VERSION 5.7 ;
  NOWIREEXTENSIONATPIN ON ;
  DIVIDERCHAR "/" ;
  BUSBITCHARS "[]" ;
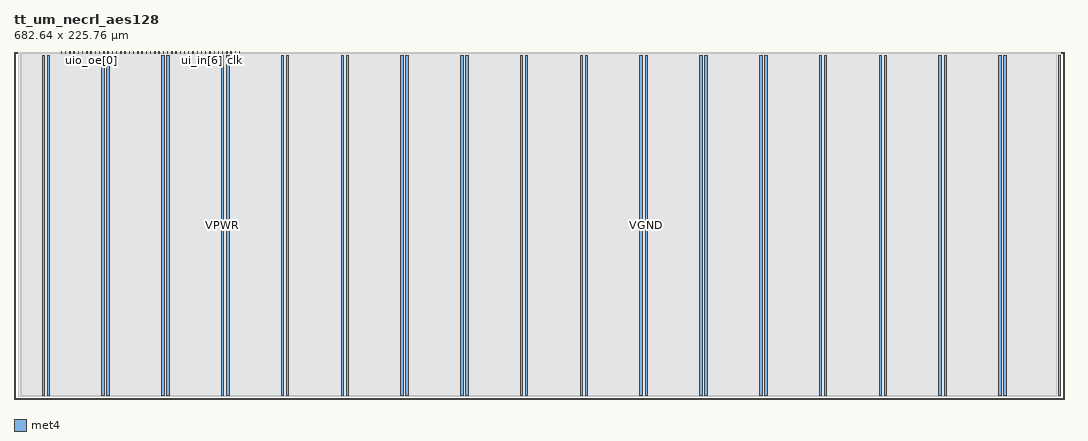
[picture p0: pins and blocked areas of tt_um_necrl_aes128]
MACRO tt_um_necrl_aes128
  CLASS BLOCK ;
  FOREIGN tt_um_necrl_aes128 ;
  ORIGIN 0.000 0.000 ;
  SIZE 682.640 BY 225.760 ;
  PIN VGND
    DIRECTION INOUT ;
    USE GROUND ;
    PORT
      LAYER met4 ;
        RECT 21.580 2.480 23.180 223.280 ;
    END
    PORT
      LAYER met4 ;
        RECT 60.450 2.480 62.050 223.280 ;
    END
    PORT
      LAYER met4 ;
        RECT 99.320 2.480 100.920 223.280 ;
    END
    PORT
      LAYER met4 ;
        RECT 138.190 2.480 139.790 223.280 ;
    END
    PORT
      LAYER met4 ;
        RECT 177.060 2.480 178.660 223.280 ;
    END
    PORT
      LAYER met4 ;
        RECT 215.930 2.480 217.530 223.280 ;
    END
    PORT
      LAYER met4 ;
        RECT 254.800 2.480 256.400 223.280 ;
    END
    PORT
      LAYER met4 ;
        RECT 293.670 2.480 295.270 223.280 ;
    END
    PORT
      LAYER met4 ;
        RECT 332.540 2.480 334.140 223.280 ;
    END
    PORT
      LAYER met4 ;
        RECT 371.410 2.480 373.010 223.280 ;
    END
    PORT
      LAYER met4 ;
        RECT 410.280 2.480 411.880 223.280 ;
    END
    PORT
      LAYER met4 ;
        RECT 449.150 2.480 450.750 223.280 ;
    END
    PORT
      LAYER met4 ;
        RECT 488.020 2.480 489.620 223.280 ;
    END
    PORT
      LAYER met4 ;
        RECT 526.890 2.480 528.490 223.280 ;
    END
    PORT
      LAYER met4 ;
        RECT 565.760 2.480 567.360 223.280 ;
    END
    PORT
      LAYER met4 ;
        RECT 604.630 2.480 606.230 223.280 ;
    END
    PORT
      LAYER met4 ;
        RECT 643.500 2.480 645.100 223.280 ;
    END
  END VGND
  PIN VPWR
    DIRECTION INOUT ;
    USE POWER ;
    PORT
      LAYER met4 ;
        RECT 18.280 2.480 19.880 223.280 ;
    END
    PORT
      LAYER met4 ;
        RECT 57.150 2.480 58.750 223.280 ;
    END
    PORT
      LAYER met4 ;
        RECT 96.020 2.480 97.620 223.280 ;
    END
    PORT
      LAYER met4 ;
        RECT 134.890 2.480 136.490 223.280 ;
    END
    PORT
      LAYER met4 ;
        RECT 173.760 2.480 175.360 223.280 ;
    END
    PORT
      LAYER met4 ;
        RECT 212.630 2.480 214.230 223.280 ;
    END
    PORT
      LAYER met4 ;
        RECT 251.500 2.480 253.100 223.280 ;
    END
    PORT
      LAYER met4 ;
        RECT 290.370 2.480 291.970 223.280 ;
    END
    PORT
      LAYER met4 ;
        RECT 329.240 2.480 330.840 223.280 ;
    END
    PORT
      LAYER met4 ;
        RECT 368.110 2.480 369.710 223.280 ;
    END
    PORT
      LAYER met4 ;
        RECT 406.980 2.480 408.580 223.280 ;
    END
    PORT
      LAYER met4 ;
        RECT 445.850 2.480 447.450 223.280 ;
    END
    PORT
      LAYER met4 ;
        RECT 484.720 2.480 486.320 223.280 ;
    END
    PORT
      LAYER met4 ;
        RECT 523.590 2.480 525.190 223.280 ;
    END
    PORT
      LAYER met4 ;
        RECT 562.460 2.480 564.060 223.280 ;
    END
    PORT
      LAYER met4 ;
        RECT 601.330 2.480 602.930 223.280 ;
    END
    PORT
      LAYER met4 ;
        RECT 640.200 2.480 641.800 223.280 ;
    END
    PORT
      LAYER met4 ;
        RECT 679.070 2.480 680.670 223.280 ;
    END
  END VPWR
  PIN clk
    DIRECTION INPUT ;
    USE SIGNAL ;
    PORT
      LAYER met4 ;
        RECT 143.830 224.760 144.130 225.760 ;
    END
  END clk
  PIN ena
    DIRECTION INPUT ;
    USE SIGNAL ;
    PORT
      LAYER met4 ;
        RECT 146.590 224.760 146.890 225.760 ;
    END
  END ena
  PIN rst_n
    DIRECTION INPUT ;
    USE SIGNAL ;
    PORT
      LAYER met4 ;
        RECT 141.070 224.760 141.370 225.760 ;
    END
  END rst_n
  PIN ui_in[0]
    DIRECTION INPUT ;
    USE SIGNAL ;
    PORT
      LAYER met4 ;
        RECT 138.310 224.760 138.610 225.760 ;
    END
  END ui_in[0]
  PIN ui_in[1]
    DIRECTION INPUT ;
    USE SIGNAL ;
    PORT
      LAYER met4 ;
        RECT 135.550 224.760 135.850 225.760 ;
    END
  END ui_in[1]
  PIN ui_in[2]
    DIRECTION INPUT ;
    USE SIGNAL ;
    PORT
      LAYER met4 ;
        RECT 132.790 224.760 133.090 225.760 ;
    END
  END ui_in[2]
  PIN ui_in[3]
    DIRECTION INPUT ;
    USE SIGNAL ;
    PORT
      LAYER met4 ;
        RECT 130.030 224.760 130.330 225.760 ;
    END
  END ui_in[3]
  PIN ui_in[4]
    DIRECTION INPUT ;
    USE SIGNAL ;
    PORT
      LAYER met4 ;
        RECT 127.270 224.760 127.570 225.760 ;
    END
  END ui_in[4]
  PIN ui_in[5]
    DIRECTION INPUT ;
    USE SIGNAL ;
    PORT
      LAYER met4 ;
        RECT 124.510 224.760 124.810 225.760 ;
    END
  END ui_in[5]
  PIN ui_in[6]
    DIRECTION INPUT ;
    USE SIGNAL ;
    PORT
      LAYER met4 ;
        RECT 121.750 224.760 122.050 225.760 ;
    END
  END ui_in[6]
  PIN ui_in[7]
    DIRECTION INPUT ;
    USE SIGNAL ;
    PORT
      LAYER met4 ;
        RECT 118.990 224.760 119.290 225.760 ;
    END
  END ui_in[7]
  PIN uio_in[0]
    DIRECTION INPUT ;
    USE SIGNAL ;
    PORT
      LAYER met4 ;
        RECT 116.230 224.760 116.530 225.760 ;
    END
  END uio_in[0]
  PIN uio_in[1]
    DIRECTION INPUT ;
    USE SIGNAL ;
    PORT
      LAYER met4 ;
        RECT 113.470 224.760 113.770 225.760 ;
    END
  END uio_in[1]
  PIN uio_in[2]
    DIRECTION INPUT ;
    USE SIGNAL ;
    PORT
      LAYER met4 ;
        RECT 110.710 224.760 111.010 225.760 ;
    END
  END uio_in[2]
  PIN uio_in[3]
    DIRECTION INPUT ;
    USE SIGNAL ;
    PORT
      LAYER met4 ;
        RECT 107.950 224.760 108.250 225.760 ;
    END
  END uio_in[3]
  PIN uio_in[4]
    DIRECTION INPUT ;
    USE SIGNAL ;
    PORT
      LAYER met4 ;
        RECT 105.190 224.760 105.490 225.760 ;
    END
  END uio_in[4]
  PIN uio_in[5]
    DIRECTION INPUT ;
    USE SIGNAL ;
    PORT
      LAYER met4 ;
        RECT 102.430 224.760 102.730 225.760 ;
    END
  END uio_in[5]
  PIN uio_in[6]
    DIRECTION INPUT ;
    USE SIGNAL ;
    PORT
      LAYER met4 ;
        RECT 99.670 224.760 99.970 225.760 ;
    END
  END uio_in[6]
  PIN uio_in[7]
    DIRECTION INPUT ;
    USE SIGNAL ;
    PORT
      LAYER met4 ;
        RECT 96.910 224.760 97.210 225.760 ;
    END
  END uio_in[7]
  PIN uio_oe[0]
    DIRECTION OUTPUT ;
    USE SIGNAL ;
    PORT
      LAYER met4 ;
        RECT 49.990 224.760 50.290 225.760 ;
    END
  END uio_oe[0]
  PIN uio_oe[1]
    DIRECTION OUTPUT ;
    USE SIGNAL ;
    PORT
      LAYER met4 ;
        RECT 47.230 224.760 47.530 225.760 ;
    END
  END uio_oe[1]
  PIN uio_oe[2]
    DIRECTION OUTPUT ;
    USE SIGNAL ;
    PORT
      LAYER met4 ;
        RECT 44.470 224.760 44.770 225.760 ;
    END
  END uio_oe[2]
  PIN uio_oe[3]
    DIRECTION OUTPUT ;
    USE SIGNAL ;
    PORT
      LAYER met4 ;
        RECT 41.710 224.760 42.010 225.760 ;
    END
  END uio_oe[3]
  PIN uio_oe[4]
    DIRECTION OUTPUT ;
    USE SIGNAL ;
    PORT
      LAYER met4 ;
        RECT 38.950 224.760 39.250 225.760 ;
    END
  END uio_oe[4]
  PIN uio_oe[5]
    DIRECTION OUTPUT ;
    USE SIGNAL ;
    PORT
      LAYER met4 ;
        RECT 36.190 224.760 36.490 225.760 ;
    END
  END uio_oe[5]
  PIN uio_oe[6]
    DIRECTION OUTPUT ;
    USE SIGNAL ;
    PORT
      LAYER met4 ;
        RECT 33.430 224.760 33.730 225.760 ;
    END
  END uio_oe[6]
  PIN uio_oe[7]
    DIRECTION OUTPUT ;
    USE SIGNAL ;
    PORT
      LAYER met4 ;
        RECT 30.670 224.760 30.970 225.760 ;
    END
  END uio_oe[7]
  PIN uio_out[0]
    DIRECTION OUTPUT ;
    USE SIGNAL ;
    PORT
      LAYER met4 ;
        RECT 72.070 224.760 72.370 225.760 ;
    END
  END uio_out[0]
  PIN uio_out[1]
    DIRECTION OUTPUT ;
    USE SIGNAL ;
    PORT
      LAYER met4 ;
        RECT 69.310 224.760 69.610 225.760 ;
    END
  END uio_out[1]
  PIN uio_out[2]
    DIRECTION OUTPUT ;
    USE SIGNAL ;
    PORT
      LAYER met4 ;
        RECT 66.550 224.760 66.850 225.760 ;
    END
  END uio_out[2]
  PIN uio_out[3]
    DIRECTION OUTPUT ;
    USE SIGNAL ;
    PORT
      LAYER met4 ;
        RECT 63.790 224.760 64.090 225.760 ;
    END
  END uio_out[3]
  PIN uio_out[4]
    DIRECTION OUTPUT ;
    USE SIGNAL ;
    PORT
      LAYER met4 ;
        RECT 61.030 224.760 61.330 225.760 ;
    END
  END uio_out[4]
  PIN uio_out[5]
    DIRECTION OUTPUT ;
    USE SIGNAL ;
    PORT
      LAYER met4 ;
        RECT 58.270 224.760 58.570 225.760 ;
    END
  END uio_out[5]
  PIN uio_out[6]
    DIRECTION OUTPUT ;
    USE SIGNAL ;
    PORT
      LAYER met4 ;
        RECT 55.510 224.760 55.810 225.760 ;
    END
  END uio_out[6]
  PIN uio_out[7]
    DIRECTION OUTPUT ;
    USE SIGNAL ;
    PORT
      LAYER met4 ;
        RECT 52.750 224.760 53.050 225.760 ;
    END
  END uio_out[7]
  PIN uo_out[0]
    DIRECTION OUTPUT ;
    USE SIGNAL ;
    PORT
      LAYER met4 ;
        RECT 94.150 224.760 94.450 225.760 ;
    END
  END uo_out[0]
  PIN uo_out[1]
    DIRECTION OUTPUT ;
    USE SIGNAL ;
    PORT
      LAYER met4 ;
        RECT 91.390 224.760 91.690 225.760 ;
    END
  END uo_out[1]
  PIN uo_out[2]
    DIRECTION OUTPUT ;
    USE SIGNAL ;
    PORT
      LAYER met4 ;
        RECT 88.630 224.760 88.930 225.760 ;
    END
  END uo_out[2]
  PIN uo_out[3]
    DIRECTION OUTPUT ;
    USE SIGNAL ;
    PORT
      LAYER met4 ;
        RECT 85.870 224.760 86.170 225.760 ;
    END
  END uo_out[3]
  PIN uo_out[4]
    DIRECTION OUTPUT ;
    USE SIGNAL ;
    PORT
      LAYER met4 ;
        RECT 83.110 224.760 83.410 225.760 ;
    END
  END uo_out[4]
  PIN uo_out[5]
    DIRECTION OUTPUT ;
    USE SIGNAL ;
    PORT
      LAYER met4 ;
        RECT 80.350 224.760 80.650 225.760 ;
    END
  END uo_out[5]
  PIN uo_out[6]
    DIRECTION OUTPUT ;
    USE SIGNAL ;
    PORT
      LAYER met4 ;
        RECT 77.590 224.760 77.890 225.760 ;
    END
  END uo_out[6]
  PIN uo_out[7]
    DIRECTION OUTPUT ;
    USE SIGNAL ;
    PORT
      LAYER met4 ;
        RECT 74.830 224.760 75.130 225.760 ;
    END
  END uo_out[7]
  OBS
      LAYER li1 ;
        RECT 2.760 2.635 679.880 223.125 ;
      LAYER met1 ;
        RECT 2.760 1.740 680.180 225.040 ;
      LAYER met2 ;
        RECT 4.240 1.710 678.860 225.070 ;
      LAYER met3 ;
        RECT 5.125 2.555 677.975 224.905 ;
      LAYER met4 ;
        RECT 5.000 2.480 677.640 224.360 ;
  END
END tt_um_necrl_aes128
END LIBRARY
